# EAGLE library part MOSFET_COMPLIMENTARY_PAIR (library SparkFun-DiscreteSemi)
Complementary pair enhancement mode MOSFET 1A and 4A A P and N channel MOSFET in a single package. Rated to breakdown at 20V. DMC2700 is 1A. SIL2308 is 4A. Link to datasheet SparkFun Products: ZX Distance and Gesture Sensor

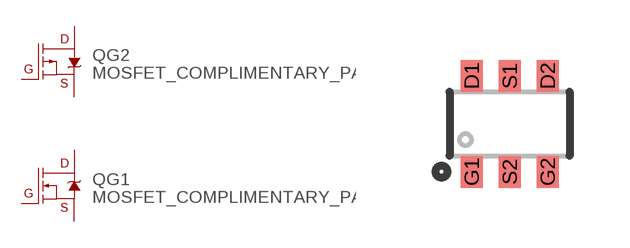
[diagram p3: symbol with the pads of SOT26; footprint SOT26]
Designator prefix Q; gates G1=LABELED-NMOS G2=LABELED-PMOS

## MOSFET_COMPLIMENTARY_PAIR-DMC2700UDM (PROD_ID: TRANS-11993)  [SOT26]
D1  G1:D
D2  G2:D
G1  G1:G
G2  G2:G
S1  G1:S
S2  G2:S

## MOSFET_COMPLIMENTARY_PAIR-SIL2308 (PROD_ID: TRANS-15717)  [SOT26]
Pads as for SOT26

## Footprint SOT26 (pad centres in mm)
Footprint for SOT-26 part DMP2240UDM
smd 0.55 x 0.8: D1 -0.95,1.2; D2 0.95,1.2; G1 -0.95,-1.2; G2 0.95,-1.2; S1 0,1.2; S2 0,-1.2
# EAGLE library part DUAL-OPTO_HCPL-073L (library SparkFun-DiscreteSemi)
HCPL-073L These high gain series couplers use a Light Emitting Diode and an integrated high gain photodetector to provide extremely high current transfer ratio between input and output. Separate pins for the photodiode and output stage result in LVTTL compatible saturation voltages and high speed operation. Where desired, the VCC and VO terminals may be tied together to achieve conventional photo-darlington operation. A base access terminal allows a gain bandwidth adjustment to be made. These optocouplers are for use in LVTTL/LVCMOS or other low power applications. A 400% minimum current transfer ratio is guaranteed over 0 to +70˚C operating range for only 0.5 mA of LED current. Digikey Link

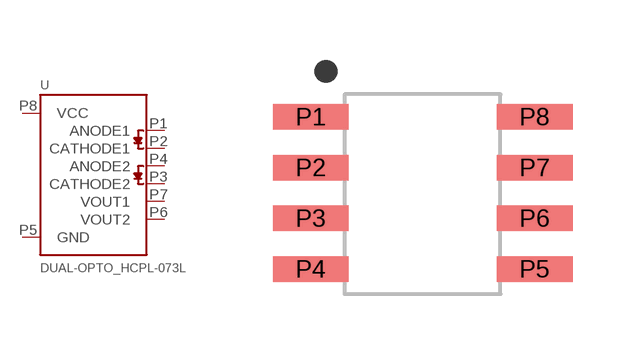
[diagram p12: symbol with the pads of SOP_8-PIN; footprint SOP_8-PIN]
Designator prefix U

## DUAL-OPTO_HCPL-073L (PROD_ID: IC-15070)  [SOP_8-PIN]
P1  ANODE1  in
P2  CATHODE1  in
P3  CATHODE2  in
P4  ANODE2  in
P5  GND  pwr
P6  VOUT2  out
P7  VOUT1  out
P8  VCC  pwr

## Footprint SOP_8-PIN (pad centres in mm)
Small Outline Package 8-Pin Mechanical Specifications Total Size: 6mm x 5mm Body Size: 4mm x 5mm Pad Size: 1.9mm x .64mm Pad Pitch: 1.270mm 8 total Pins
smd 1.9 x 0.64: P1 -2.921,2.032; P2 -2.921,0.762; P3 -2.921,-0.508; P4 -2.921,-1.778; P5 2.679,-1.778; P6 2.679,-0.508; P7 2.679,0.762; P8 2.679,2.032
